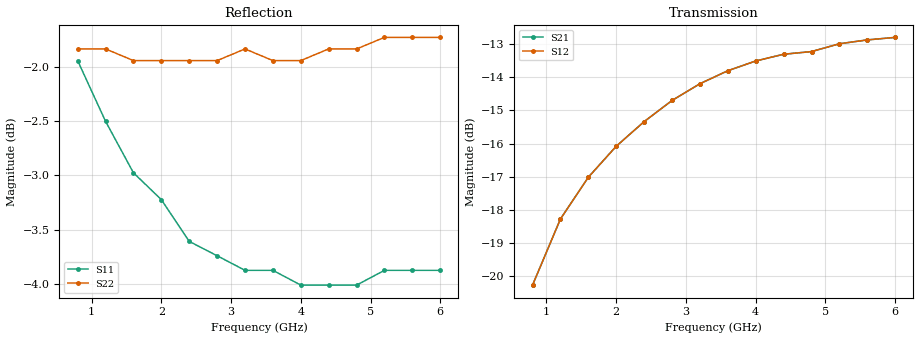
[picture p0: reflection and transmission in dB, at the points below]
!  MGA-72543 S PARAMETERS
!  Vd=0V  Id=0 mA  LAST UPDATED 01-27-99
# ghz s ma r 50
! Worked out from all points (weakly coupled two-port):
!   14 points, 800 MHz to 6 GHz, reference 50 ohm
!   highest |S21| = -12.80 dB at 6 GHz (marker M1); lowest = -20.3 dB at 800 MHz (marker M2)
!   lowest |S11| = -4.0 dB at 4 GHz (marker M3), VSWR 4.41, Z = 13.5 + j20.9 ohm
!   |S11| at or under -10 dB: nowhere
!   |S22| runs from -1.9 to -1.7 dB; largest |S21 - S12| = 0
!   S11 on the Smith chart (normalised r, x): 800 MHz: 0.23, -1.01; 1.6 GHz: 0.19, -0.36; 2 GHz: 0.19, -0.20; 3.2 GHz: 0.23, +0.19; 4.4 GHz: 0.29, +0.53; 6 GHz: 0.45, +0.97
0.8  0.8 -88.0  0.097 50.0  0.097 50.0  0.81 167.0
1.2  0.75 -117.0  0.122 39.0  0.122 39.0  0.81 160.0
1.6  0.71 -139.0  0.141 31.0  0.141 31.0  0.8 152.0
2  0.69 -157.0  0.157 25.0  0.157 25.0  0.8 145.0
2.4  0.66 -174.0  0.171 18.0  0.171 18.0  0.8 137.0
2.8  0.65 171.0  0.184 12.0  0.184 12.0  0.8 129.0
3.2  0.64 157.0  0.195 6.0  0.195 6.0  0.81 122.0
3.6  0.64 144.0  0.204 0.0  0.204 0.0  0.8 115.0
4  0.63 132.0  0.211 -5.0  0.211 -5.0  0.8 108.0
4.4  0.63 121.0  0.216 -11.0  0.216 -11.0  0.81 102.0
4.8  0.63 112.0  0.218 -15.0  0.218 -15.0  0.81 95.0
5.2  0.64 103.0  0.224 -20.0  0.224 -20.0  0.82 89.0
5.6  0.64 94.0  0.227 -26.0  0.227 -26.0  0.82 83.0
6  0.64 86.0  0.229 -31.0  0.229 -31.0  0.82 76.0
